VERSION 5.7 ;
BUSBITCHARS "[]" ;
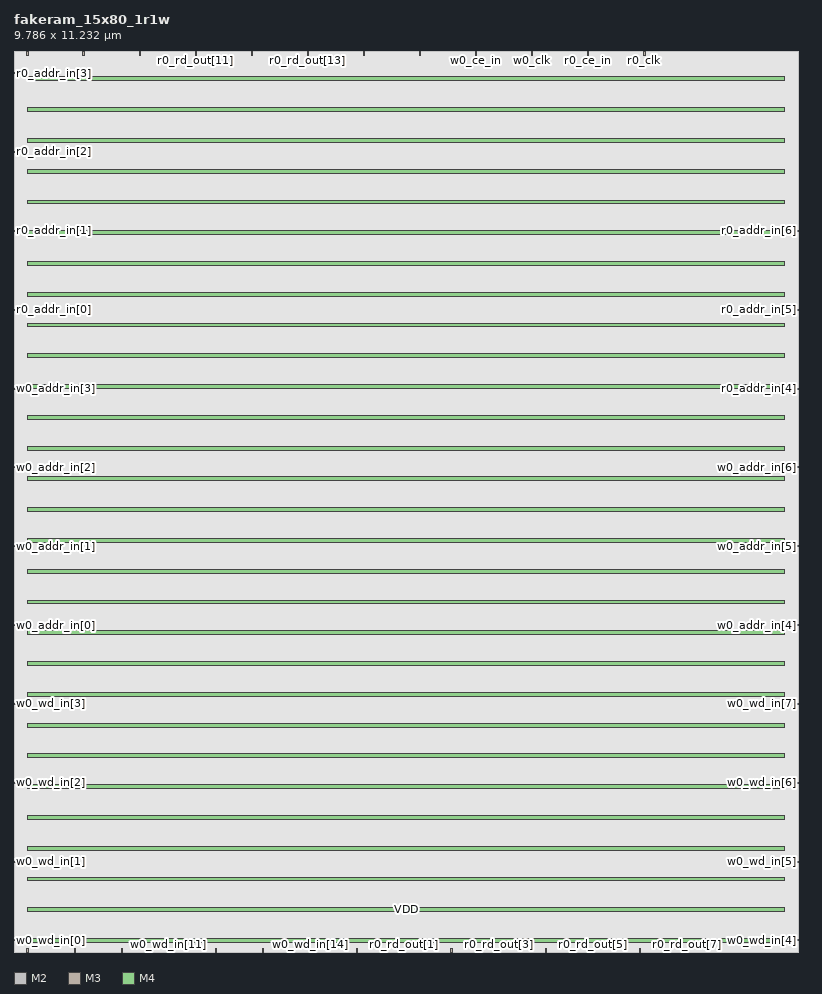
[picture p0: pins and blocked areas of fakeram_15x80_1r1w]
MACRO fakeram_15x80_1r1w
  FOREIGN fakeram_15x80_1r1w 0 0 ;
  SYMMETRY X Y R90 ;
  SIZE 9.786 BY 11.232 ;
  CLASS BLOCK ;
  PIN w0_wd_in[0]
    DIRECTION INPUT ;
    USE SIGNAL ;
    SHAPE ABUTMENT ;
    PORT
      LAYER M2 ;
      RECT 0.000 0.138 0.036 0.150 ;
    END
  END w0_wd_in[0]
  PIN w0_wd_in[1]
    DIRECTION INPUT ;
    USE SIGNAL ;
    SHAPE ABUTMENT ;
    PORT
      LAYER M2 ;
      RECT 0.000 1.122 0.036 1.134 ;
    END
  END w0_wd_in[1]
  PIN w0_wd_in[2]
    DIRECTION INPUT ;
    USE SIGNAL ;
    SHAPE ABUTMENT ;
    PORT
      LAYER M2 ;
      RECT 0.000 2.106 0.036 2.118 ;
    END
  END w0_wd_in[2]
  PIN w0_wd_in[3]
    DIRECTION INPUT ;
    USE SIGNAL ;
    SHAPE ABUTMENT ;
    PORT
      LAYER M2 ;
      RECT 0.000 3.090 0.036 3.102 ;
    END
  END w0_wd_in[3]
  PIN w0_wd_in[4]
    DIRECTION INPUT ;
    USE SIGNAL ;
    SHAPE ABUTMENT ;
    PORT
      LAYER M2 ;
      RECT 9.750 0.138 9.786 0.150 ;
    END
  END w0_wd_in[4]
  PIN w0_wd_in[5]
    DIRECTION INPUT ;
    USE SIGNAL ;
    SHAPE ABUTMENT ;
    PORT
      LAYER M2 ;
      RECT 9.750 1.122 9.786 1.134 ;
    END
  END w0_wd_in[5]
  PIN w0_wd_in[6]
    DIRECTION INPUT ;
    USE SIGNAL ;
    SHAPE ABUTMENT ;
    PORT
      LAYER M2 ;
      RECT 9.750 2.106 9.786 2.118 ;
    END
  END w0_wd_in[6]
  PIN w0_wd_in[7]
    DIRECTION INPUT ;
    USE SIGNAL ;
    SHAPE ABUTMENT ;
    PORT
      LAYER M2 ;
      RECT 9.750 3.090 9.786 3.102 ;
    END
  END w0_wd_in[7]
  PIN w0_wd_in[8]
    DIRECTION INPUT ;
    USE SIGNAL ;
    SHAPE ABUTMENT ;
    PORT
      LAYER M3 ;
      RECT 0.161 0.000 0.175 0.042 ;
    END
  END w0_wd_in[8]
  PIN w0_wd_in[9]
    DIRECTION INPUT ;
    USE SIGNAL ;
    SHAPE ABUTMENT ;
    PORT
      LAYER M3 ;
      RECT 0.749 0.000 0.763 0.042 ;
    END
  END w0_wd_in[9]
  PIN w0_wd_in[10]
    DIRECTION INPUT ;
    USE SIGNAL ;
    SHAPE ABUTMENT ;
    PORT
      LAYER M3 ;
      RECT 1.337 0.000 1.351 0.042 ;
    END
  END w0_wd_in[10]
  PIN w0_wd_in[11]
    DIRECTION INPUT ;
    USE SIGNAL ;
    SHAPE ABUTMENT ;
    PORT
      LAYER M3 ;
      RECT 1.925 0.000 1.939 0.042 ;
    END
  END w0_wd_in[11]
  PIN w0_wd_in[12]
    DIRECTION INPUT ;
    USE SIGNAL ;
    SHAPE ABUTMENT ;
    PORT
      LAYER M3 ;
      RECT 2.513 0.000 2.527 0.042 ;
    END
  END w0_wd_in[12]
  PIN w0_wd_in[13]
    DIRECTION INPUT ;
    USE SIGNAL ;
    SHAPE ABUTMENT ;
    PORT
      LAYER M3 ;
      RECT 3.101 0.000 3.115 0.042 ;
    END
  END w0_wd_in[13]
  PIN w0_wd_in[14]
    DIRECTION INPUT ;
    USE SIGNAL ;
    SHAPE ABUTMENT ;
    PORT
      LAYER M3 ;
      RECT 3.689 0.000 3.703 0.042 ;
    END
  END w0_wd_in[14]
  PIN r0_rd_out[0]
    DIRECTION OUTPUT ;
    USE SIGNAL ;
    SHAPE ABUTMENT ;
    PORT
      LAYER M3 ;
      RECT 4.277 0.000 4.291 0.042 ;
    END
  END r0_rd_out[0]
  PIN r0_rd_out[1]
    DIRECTION OUTPUT ;
    USE SIGNAL ;
    SHAPE ABUTMENT ;
    PORT
      LAYER M3 ;
      RECT 4.865 0.000 4.879 0.042 ;
    END
  END r0_rd_out[1]
  PIN r0_rd_out[2]
    DIRECTION OUTPUT ;
    USE SIGNAL ;
    SHAPE ABUTMENT ;
    PORT
      LAYER M3 ;
      RECT 5.453 0.000 5.467 0.042 ;
    END
  END r0_rd_out[2]
  PIN r0_rd_out[3]
    DIRECTION OUTPUT ;
    USE SIGNAL ;
    SHAPE ABUTMENT ;
    PORT
      LAYER M3 ;
      RECT 6.041 0.000 6.055 0.042 ;
    END
  END r0_rd_out[3]
  PIN r0_rd_out[4]
    DIRECTION OUTPUT ;
    USE SIGNAL ;
    SHAPE ABUTMENT ;
    PORT
      LAYER M3 ;
      RECT 6.629 0.000 6.643 0.042 ;
    END
  END r0_rd_out[4]
  PIN r0_rd_out[5]
    DIRECTION OUTPUT ;
    USE SIGNAL ;
    SHAPE ABUTMENT ;
    PORT
      LAYER M3 ;
      RECT 7.217 0.000 7.231 0.042 ;
    END
  END r0_rd_out[5]
  PIN r0_rd_out[6]
    DIRECTION OUTPUT ;
    USE SIGNAL ;
    SHAPE ABUTMENT ;
    PORT
      LAYER M3 ;
      RECT 7.805 0.000 7.819 0.042 ;
    END
  END r0_rd_out[6]
  PIN r0_rd_out[7]
    DIRECTION OUTPUT ;
    USE SIGNAL ;
    SHAPE ABUTMENT ;
    PORT
      LAYER M3 ;
      RECT 8.393 0.000 8.407 0.042 ;
    END
  END r0_rd_out[7]
  PIN r0_rd_out[8]
    DIRECTION OUTPUT ;
    USE SIGNAL ;
    SHAPE ABUTMENT ;
    PORT
      LAYER M3 ;
      RECT 0.161 11.190 0.175 11.232 ;
    END
  END r0_rd_out[8]
  PIN r0_rd_out[9]
    DIRECTION OUTPUT ;
    USE SIGNAL ;
    SHAPE ABUTMENT ;
    PORT
      LAYER M3 ;
      RECT 0.861 11.190 0.875 11.232 ;
    END
  END r0_rd_out[9]
  PIN r0_rd_out[10]
    DIRECTION OUTPUT ;
    USE SIGNAL ;
    SHAPE ABUTMENT ;
    PORT
      LAYER M3 ;
      RECT 1.561 11.190 1.575 11.232 ;
    END
  END r0_rd_out[10]
  PIN r0_rd_out[11]
    DIRECTION OUTPUT ;
    USE SIGNAL ;
    SHAPE ABUTMENT ;
    PORT
      LAYER M3 ;
      RECT 2.261 11.190 2.275 11.232 ;
    END
  END r0_rd_out[11]
  PIN r0_rd_out[12]
    DIRECTION OUTPUT ;
    USE SIGNAL ;
    SHAPE ABUTMENT ;
    PORT
      LAYER M3 ;
      RECT 2.961 11.190 2.975 11.232 ;
    END
  END r0_rd_out[12]
  PIN r0_rd_out[13]
    DIRECTION OUTPUT ;
    USE SIGNAL ;
    SHAPE ABUTMENT ;
    PORT
      LAYER M3 ;
      RECT 3.661 11.190 3.675 11.232 ;
    END
  END r0_rd_out[13]
  PIN r0_rd_out[14]
    DIRECTION OUTPUT ;
    USE SIGNAL ;
    SHAPE ABUTMENT ;
    PORT
      LAYER M3 ;
      RECT 4.361 11.190 4.375 11.232 ;
    END
  END r0_rd_out[14]
  PIN w0_addr_in[0]
    DIRECTION INPUT ;
    USE SIGNAL ;
    SHAPE ABUTMENT ;
    PORT
      LAYER M2 ;
      RECT 0.000 4.074 0.036 4.086 ;
    END
  END w0_addr_in[0]
  PIN w0_addr_in[1]
    DIRECTION INPUT ;
    USE SIGNAL ;
    SHAPE ABUTMENT ;
    PORT
      LAYER M2 ;
      RECT 0.000 5.058 0.036 5.070 ;
    END
  END w0_addr_in[1]
  PIN w0_addr_in[2]
    DIRECTION INPUT ;
    USE SIGNAL ;
    SHAPE ABUTMENT ;
    PORT
      LAYER M2 ;
      RECT 0.000 6.042 0.036 6.054 ;
    END
  END w0_addr_in[2]
  PIN w0_addr_in[3]
    DIRECTION INPUT ;
    USE SIGNAL ;
    SHAPE ABUTMENT ;
    PORT
      LAYER M2 ;
      RECT 0.000 7.026 0.036 7.038 ;
    END
  END w0_addr_in[3]
  PIN w0_addr_in[4]
    DIRECTION INPUT ;
    USE SIGNAL ;
    SHAPE ABUTMENT ;
    PORT
      LAYER M2 ;
      RECT 9.750 4.074 9.786 4.086 ;
    END
  END w0_addr_in[4]
  PIN w0_addr_in[5]
    DIRECTION INPUT ;
    USE SIGNAL ;
    SHAPE ABUTMENT ;
    PORT
      LAYER M2 ;
      RECT 9.750 5.058 9.786 5.070 ;
    END
  END w0_addr_in[5]
  PIN w0_addr_in[6]
    DIRECTION INPUT ;
    USE SIGNAL ;
    SHAPE ABUTMENT ;
    PORT
      LAYER M2 ;
      RECT 9.750 6.042 9.786 6.054 ;
    END
  END w0_addr_in[6]
  PIN r0_addr_in[0]
    DIRECTION INPUT ;
    USE SIGNAL ;
    SHAPE ABUTMENT ;
    PORT
      LAYER M2 ;
      RECT 0.000 8.010 0.036 8.022 ;
    END
  END r0_addr_in[0]
  PIN r0_addr_in[1]
    DIRECTION INPUT ;
    USE SIGNAL ;
    SHAPE ABUTMENT ;
    PORT
      LAYER M2 ;
      RECT 0.000 8.994 0.036 9.006 ;
    END
  END r0_addr_in[1]
  PIN r0_addr_in[2]
    DIRECTION INPUT ;
    USE SIGNAL ;
    SHAPE ABUTMENT ;
    PORT
      LAYER M2 ;
      RECT 0.000 9.978 0.036 9.990 ;
    END
  END r0_addr_in[2]
  PIN r0_addr_in[3]
    DIRECTION INPUT ;
    USE SIGNAL ;
    SHAPE ABUTMENT ;
    PORT
      LAYER M2 ;
      RECT 0.000 10.962 0.036 10.974 ;
    END
  END r0_addr_in[3]
  PIN r0_addr_in[4]
    DIRECTION INPUT ;
    USE SIGNAL ;
    SHAPE ABUTMENT ;
    PORT
      LAYER M2 ;
      RECT 9.750 7.026 9.786 7.038 ;
    END
  END r0_addr_in[4]
  PIN r0_addr_in[5]
    DIRECTION INPUT ;
    USE SIGNAL ;
    SHAPE ABUTMENT ;
    PORT
      LAYER M2 ;
      RECT 9.750 8.010 9.786 8.022 ;
    END
  END r0_addr_in[5]
  PIN r0_addr_in[6]
    DIRECTION INPUT ;
    USE SIGNAL ;
    SHAPE ABUTMENT ;
    PORT
      LAYER M2 ;
      RECT 9.750 8.994 9.786 9.006 ;
    END
  END r0_addr_in[6]
  PIN w0_we_in
    DIRECTION INPUT ;
    USE SIGNAL ;
    SHAPE ABUTMENT ;
    PORT
      LAYER M3 ;
      RECT 5.061 11.190 5.075 11.232 ;
    END
  END w0_we_in
  PIN w0_ce_in
    DIRECTION INPUT ;
    USE SIGNAL ;
    SHAPE ABUTMENT ;
    PORT
      LAYER M3 ;
      RECT 5.761 11.190 5.775 11.232 ;
    END
  END w0_ce_in
  PIN w0_clk
    DIRECTION INPUT ;
    USE SIGNAL ;
    SHAPE ABUTMENT ;
    PORT
      LAYER M3 ;
      RECT 6.461 11.190 6.475 11.232 ;
    END
  END w0_clk
  PIN r0_ce_in
    DIRECTION INPUT ;
    USE SIGNAL ;
    SHAPE ABUTMENT ;
    PORT
      LAYER M3 ;
      RECT 7.161 11.190 7.175 11.232 ;
    END
  END r0_ce_in
  PIN r0_clk
    DIRECTION INPUT ;
    USE SIGNAL ;
    SHAPE ABUTMENT ;
    PORT
      LAYER M3 ;
      RECT 7.861 11.190 7.875 11.232 ;
    END
  END r0_clk
  PIN VSS
    DIRECTION INOUT ;
    USE GROUND ;
    PORT
      LAYER M4 ;
      RECT 0.168 0.120 9.618 0.168 ;
      RECT 0.168 0.504 9.618 0.552 ;
      RECT 0.168 0.888 9.618 0.936 ;
      RECT 0.168 1.272 9.618 1.320 ;
      RECT 0.168 1.656 9.618 1.704 ;
      RECT 0.168 2.040 9.618 2.088 ;
      RECT 0.168 2.424 9.618 2.472 ;
      RECT 0.168 2.808 9.618 2.856 ;
      RECT 0.168 3.192 9.618 3.240 ;
      RECT 0.168 3.576 9.618 3.624 ;
      RECT 0.168 3.960 9.618 4.008 ;
      RECT 0.168 4.344 9.618 4.392 ;
      RECT 0.168 4.728 9.618 4.776 ;
      RECT 0.168 5.112 9.618 5.160 ;
      RECT 0.168 5.496 9.618 5.544 ;
      RECT 0.168 5.880 9.618 5.928 ;
      RECT 0.168 6.264 9.618 6.312 ;
      RECT 0.168 6.648 9.618 6.696 ;
      RECT 0.168 7.032 9.618 7.080 ;
      RECT 0.168 7.416 9.618 7.464 ;
      RECT 0.168 7.800 9.618 7.848 ;
      RECT 0.168 8.184 9.618 8.232 ;
      RECT 0.168 8.568 9.618 8.616 ;
      RECT 0.168 8.952 9.618 9.000 ;
      RECT 0.168 9.336 9.618 9.384 ;
      RECT 0.168 9.720 9.618 9.768 ;
      RECT 0.168 10.104 9.618 10.152 ;
      RECT 0.168 10.488 9.618 10.536 ;
      RECT 0.168 10.872 9.618 10.920 ;
    END
  END VSS
  PIN VDD
    DIRECTION INOUT ;
    USE POWER ;
    PORT
      LAYER M4 ;
      RECT 0.168 0.120 9.618 0.168 ;
      RECT 0.168 0.504 9.618 0.552 ;
      RECT 0.168 0.888 9.618 0.936 ;
      RECT 0.168 1.272 9.618 1.320 ;
      RECT 0.168 1.656 9.618 1.704 ;
      RECT 0.168 2.040 9.618 2.088 ;
      RECT 0.168 2.424 9.618 2.472 ;
      RECT 0.168 2.808 9.618 2.856 ;
      RECT 0.168 3.192 9.618 3.240 ;
      RECT 0.168 3.576 9.618 3.624 ;
      RECT 0.168 3.960 9.618 4.008 ;
      RECT 0.168 4.344 9.618 4.392 ;
      RECT 0.168 4.728 9.618 4.776 ;
      RECT 0.168 5.112 9.618 5.160 ;
      RECT 0.168 5.496 9.618 5.544 ;
      RECT 0.168 5.880 9.618 5.928 ;
      RECT 0.168 6.264 9.618 6.312 ;
      RECT 0.168 6.648 9.618 6.696 ;
      RECT 0.168 7.032 9.618 7.080 ;
      RECT 0.168 7.416 9.618 7.464 ;
      RECT 0.168 7.800 9.618 7.848 ;
      RECT 0.168 8.184 9.618 8.232 ;
      RECT 0.168 8.568 9.618 8.616 ;
      RECT 0.168 8.952 9.618 9.000 ;
      RECT 0.168 9.336 9.618 9.384 ;
      RECT 0.168 9.720 9.618 9.768 ;
      RECT 0.168 10.104 9.618 10.152 ;
      RECT 0.168 10.488 9.618 10.536 ;
      RECT 0.168 10.872 9.618 10.920 ;
    END
  END VDD
  OBS
    LAYER M1 ;
    RECT 0 0 9.786 11.232 ;
    LAYER M2 ;
    RECT 0 0 9.786 11.232 ;
    LAYER M3 ;
    RECT 0 0 9.786 11.232 ;
    LAYER M4 ;
    RECT 0 0 9.786 11.232 ;
  END
END fakeram_15x80_1r1w

END LIBRARY
